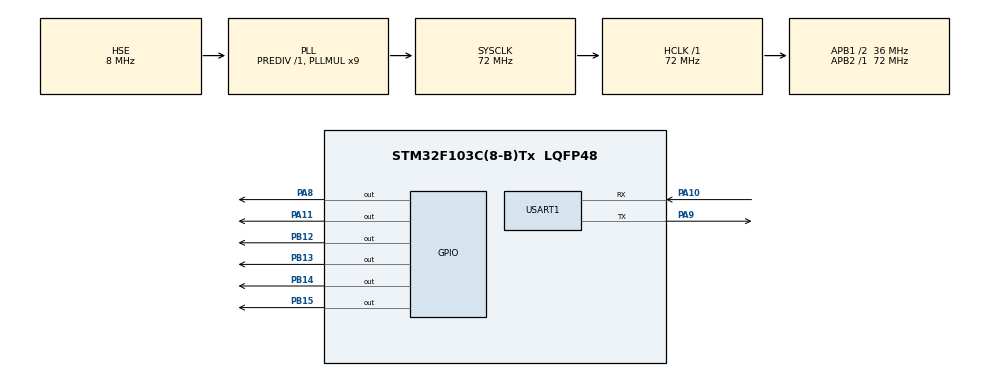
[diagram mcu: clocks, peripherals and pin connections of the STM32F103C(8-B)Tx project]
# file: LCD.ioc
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Mcu.Family=STM32F1
Mcu.Name=STM32F103C(8-B)Tx
Mcu.Package=LQFP48
NVIC.PriorityGroup=NVIC_PRIORITYGROUP_4
NVIC.USART1_IRQn=true\:0\:0\:false\:false\:true\:true\:true\:true
PA10.Mode=Asynchronous
PA10.Signal=USART1_RX
PA11.Signal=GPIO_Output
PA13.Mode=Serial_Wire
PA13.Signal=SYS_JTMS-SWDIO
PA14.Mode=Serial_Wire
PA14.Signal=SYS_JTCK-SWCLK
PA8.Signal=GPIO_Output
PA9.Mode=Asynchronous
PA9.Signal=USART1_TX
PB12.Signal=GPIO_Output
PB13.Signal=GPIO_Output
PB14.Signal=GPIO_Output
PB15.Signal=GPIO_Output
PD0-OSC_IN.Mode=HSE-External-Oscillator
PD0-OSC_IN.Signal=RCC_OSC_IN
PD1-OSC_OUT.Mode=HSE-External-Oscillator
PD1-OSC_OUT.Signal=RCC_OSC_OUT
ProjectManager.HeapSize=0x200
ProjectManager.StackSize=0x400
ProjectManager.TargetToolchain=STM32CubeIDE
RCC.AHBFreq_Value=72000000
RCC.APB1CLKDivider=RCC_HCLK_DIV2
RCC.APB1Freq_Value=36000000
RCC.APB1TimFreq_Value=72000000
RCC.APB2Freq_Value=72000000
RCC.APB2TimFreq_Value=72000000
RCC.HCLKFreq_Value=72000000
RCC.PLLMUL=RCC_PLL_MUL9
RCC.PLLSourceVirtual=RCC_PLLSOURCE_HSE
RCC.SYSCLKFreq_VALUE=72000000
RCC.SYSCLKSource=RCC_SYSCLKSOURCE_PLLCLK
RCC.USBFreq_Value=72000000
TIM1.Period=0xffff-1
TIM1.Prescaler=72-1
USART1.VirtualMode=VM_ASYNC
VP_RTC_VS_RTC_Activate.Mode=RTC_Enabled
VP_TIM1_VS_ClockSourceINT.Mode=Internal
board=custom

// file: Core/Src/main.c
#include "main.h"
#include "LCD1602.h"
#include "ringQueue.h"

// UART Interface
uint8_t B_Rx;  // Buffer for receiving a single character
uint8_t B_C4COLUMN = 0;
uint8_t B_C4ROW = 0;

RingBuffer GPS_Buffer;
uint8_t GPS_Data[RB_QUEUE_SIZE];
static int GPS_Data_pos = 0;

UART_HandleTypeDef huart1;
TIM_HandleTypeDef htim1;
RTC_HandleTypeDef hrtc;

void SystemClock_Config(void);

static void MX_GPIO_Init(void);

static void MX_TIM1_Init(void);

static void MX_USART1_UART_Init(void);

static void MX_RTC_Init(void);

void uint8_to_str(uint8_t num, char *str) {
    int i = 0;
    char temp[4];  // Max "255" + '\0'

    do {
        temp[i++] = (num % 10) + '0';  // Extract last digit
        num /= 10;
    } while (num);

    // Reverse the string
    int j = 0;
    while (i > 0) {
        str[j++] = temp[--i];
    }
    str[j] = '\0';  // Null-terminate
}

void get_current_time() {
    RTC_TimeTypeDef sTime;
    HAL_RTC_GetTime(&hrtc, &sTime, RTC_FORMAT_BIN);
    char time[8];
    lcd_clear();
    lcd_put_cur(0, 0);
    lcd_send_string("[TIME]");

    uint8_to_str(sTime.Hours, time);
    lcd_put_cur(0, 7);
    lcd_send_string(time);
    lcd_send_string(":");

    uint8_to_str(sTime.Minutes, time);
    lcd_put_cur(0, 10);
    lcd_send_string(time);
    lcd_send_string(":");

    uint8_to_str(sTime.Seconds, time);
    lcd_put_cur(0, 13);
    lcd_send_string(time);
}

int main(void) {
    HAL_Init();
    SystemClock_Config();
    MX_GPIO_Init();
    MX_TIM1_Init();
    HAL_TIM_Base_Start(&htim1);
    MX_USART1_UART_Init();
    MX_RTC_Init();
    // Main Screen
    lcd_init();
    // UART Interface
    HAL_UART_Receive_IT(&huart1, &B_Rx, 1);
    rb_init(&GPS_Buffer);
    // Main Loop
    while (1) {
    }
}

void HAL_UART_RxCpltCallback(UART_HandleTypeDef *huart) {
    if (huart->Instance == USART1) {
//        rb_enqueue(&GPS_Buffer, B_Rx)
        if (B_C4COLUMN > 15) {
            B_C4COLUMN = 0;
            // Toggle row between 0 and 1
            B_C4ROW = (B_C4ROW == 0) ? 1 : 0;
            // Clear the new row
            lcd_put_cur(B_C4ROW, B_C4COLUMN);
            lcd_send_string("                ");
        }
        lcd_put_cur(B_C4ROW, B_C4COLUMN);
        lcd_send_data(B_Rx);
        B_C4COLUMN++;
        // Restart UART reception (so it keeps working in background)
        HAL_UART_Receive_IT(&huart1, &B_Rx, 1);

        // Send acknowledgment
        HAL_UART_Transmit(&huart1, (uint8_t *) "ok\r\n", 4, 100);
    }
}

void SystemClock_Config(void) {
    RCC_OscInitTypeDef RCC_OscInitStruct = {0};
    RCC_ClkInitTypeDef RCC_ClkInitStruct = {0};
    RCC_PeriphCLKInitTypeDef PeriphClkInit = {0};

    /** Initializes the CPU, AHB and APB busses clocks
    */
    RCC_OscInitStruct.OscillatorType = RCC_OSCILLATORTYPE_LSI | RCC_OSCILLATORTYPE_HSE;
    RCC_OscInitStruct.HSEState = RCC_HSE_ON;
    RCC_OscInitStruct.HSEPredivValue = RCC_HSE_PREDIV_DIV1;
    RCC_OscInitStruct.HSIState = RCC_HSI_ON;
    RCC_OscInitStruct.LSIState = RCC_LSI_ON;
    RCC_OscInitStruct.PLL.PLLState = RCC_PLL_ON;
    RCC_OscInitStruct.PLL.PLLSource = RCC_PLLSOURCE_HSE;
    RCC_OscInitStruct.PLL.PLLMUL = RCC_PLL_MUL9;
    if (HAL_RCC_OscConfig(&RCC_OscInitStruct) != HAL_OK) {
        Error_Handler();
    }
    /** Initializes the CPU, AHB and APB busses clocks
    */
    RCC_ClkInitStruct.ClockType = RCC_CLOCKTYPE_HCLK | RCC_CLOCKTYPE_SYSCLK
                                  | RCC_CLOCKTYPE_PCLK1 | RCC_CLOCKTYPE_PCLK2;
    RCC_ClkInitStruct.SYSCLKSource = RCC_SYSCLKSOURCE_PLLCLK;
    RCC_ClkInitStruct.AHBCLKDivider = RCC_SYSCLK_DIV1;
    RCC_ClkInitStruct.APB1CLKDivider = RCC_HCLK_DIV2;
    RCC_ClkInitStruct.APB2CLKDivider = RCC_HCLK_DIV1;

    if (HAL_RCC_ClockConfig(&RCC_ClkInitStruct, FLASH_LATENCY_2) != HAL_OK) {
        Error_Handler();
    }
    PeriphClkInit.PeriphClockSelection = RCC_PERIPHCLK_RTC;
    PeriphClkInit.RTCClockSelection = RCC_RTCCLKSOURCE_LSI;
    if (HAL_RCCEx_PeriphCLKConfig(&PeriphClkInit) != HAL_OK) {
        Error_Handler();
    }
}

static void MX_RTC_Init(void) {
    /** Initialize RTC Only
    */
    hrtc.Instance = RTC;
    hrtc.Init.AsynchPrediv = RTC_AUTO_1_SECOND;
    hrtc.Init.OutPut = RTC_OUTPUTSOURCE_ALARM;
    if (HAL_RTC_Init(&hrtc) != HAL_OK) {
        Error_Handler();
    }
}

static void MX_TIM1_Init(void) {

    TIM_ClockConfigTypeDef sClockSourceConfig = {0};
    TIM_MasterConfigTypeDef sMasterConfig = {0};

    htim1.Instance = TIM1;
    htim1.Init.Prescaler = 72 - 1;
    htim1.Init.CounterMode = TIM_COUNTERMODE_UP;
    htim1.Init.Period = 0xffff - 1;
    htim1.Init.ClockDivision = TIM_CLOCKDIVISION_DIV1;
    htim1.Init.RepetitionCounter = 0;
    htim1.Init.AutoReloadPreload = TIM_AUTORELOAD_PRELOAD_DISABLE;
    if (HAL_TIM_Base_Init(&htim1) != HAL_OK) {
        Error_Handler();
    }
    sClockSourceConfig.ClockSource = TIM_CLOCKSOURCE_INTERNAL;
    if (HAL_TIM_ConfigClockSource(&htim1, &sClockSourceConfig) != HAL_OK) {
        Error_Handler();
    }
    sMasterConfig.MasterOutputTrigger = TIM_TRGO_RESET;
    sMasterConfig.MasterSlaveMode = TIM_MASTERSLAVEMODE_DISABLE;
    if (HAL_TIMEx_MasterConfigSynchronization(&htim1, &sMasterConfig) != HAL_OK) {
        Error_Handler();
    }

}

static void MX_USART1_UART_Init(void) {
    huart1.Instance = USART1;
    huart1.Init.BaudRate = 115200;
    huart1.Init.WordLength = UART_WORDLENGTH_8B;
    huart1.Init.StopBits = UART_STOPBITS_1;
    huart1.Init.Parity = UART_PARITY_NONE;
    huart1.Init.Mode = UART_MODE_TX_RX;
    huart1.Init.HwFlowCtl = UART_HWCONTROL_NONE;
    huart1.Init.OverSampling = UART_OVERSAMPLING_16;
    if (HAL_UART_Init(&huart1) != HAL_OK) {
        Error_Handler();
    }
}

static void MX_GPIO_Init(void) {
    GPIO_InitTypeDef GPIO_InitStruct = {0};

    /* GPIO Ports Clock Enable */
    __HAL_RCC_GPIOD_CLK_ENABLE();
    __HAL_RCC_GPIOB_CLK_ENABLE();
    __HAL_RCC_GPIOA_CLK_ENABLE();
    __HAL_RCC_GPIOC_CLK_ENABLE();

    /*Configure GPIO pin Output Level */
    HAL_GPIO_WritePin(GPIOC, GPIO_PIN_13 | GPIO_PIN_14 | GPIO_PIN_15, GPIO_PIN_RESET);
    HAL_GPIO_WritePin(GPIOB, GPIO_PIN_12 | GPIO_PIN_13 | GPIO_PIN_14 | GPIO_PIN_15, GPIO_PIN_RESET);
    HAL_GPIO_WritePin(GPIOA, GPIO_PIN_2 | GPIO_PIN_8 | GPIO_PIN_11, GPIO_PIN_RESET);

    /*Configure GPIO pins : PC13 PC14 PC15 */
    GPIO_InitStruct.Pin = GPIO_PIN_13 | GPIO_PIN_14 | GPIO_PIN_15;
    GPIO_InitStruct.Mode = GPIO_MODE_OUTPUT_PP;
    GPIO_InitStruct.Pull = GPIO_NOPULL;
    GPIO_InitStruct.Speed = GPIO_SPEED_FREQ_LOW;
    HAL_GPIO_Init(GPIOC, &GPIO_InitStruct);

    /*Configure GPIO pins : PB12 PB13 PB14 PB15 */
    GPIO_InitStruct.Pin = GPIO_PIN_12 | GPIO_PIN_13 | GPIO_PIN_14 | GPIO_PIN_15;
    GPIO_InitStruct.Mode = GPIO_MODE_OUTPUT_PP;
    GPIO_InitStruct.Pull = GPIO_NOPULL;
    GPIO_InitStruct.Speed = GPIO_SPEED_FREQ_LOW;
    HAL_GPIO_Init(GPIOB, &GPIO_InitStruct);

    /*Configure GPIO pins : PA8 PA11 */
    GPIO_InitStruct.Pin = GPIO_PIN_2 | GPIO_PIN_8 | GPIO_PIN_11;
    GPIO_InitStruct.Mode = GPIO_MODE_OUTPUT_PP;
    GPIO_InitStruct.Pull = GPIO_NOPULL;
    GPIO_InitStruct.Speed = GPIO_SPEED_FREQ_LOW;
    HAL_GPIO_Init(GPIOA, &GPIO_InitStruct);

}

void Error_Handler(void) {
}
